VERSION 5.7 ;
  NOWIREEXTENSIONATPIN ON ;
  DIVIDERCHAR "/" ;
  BUSBITCHARS "[]" ;
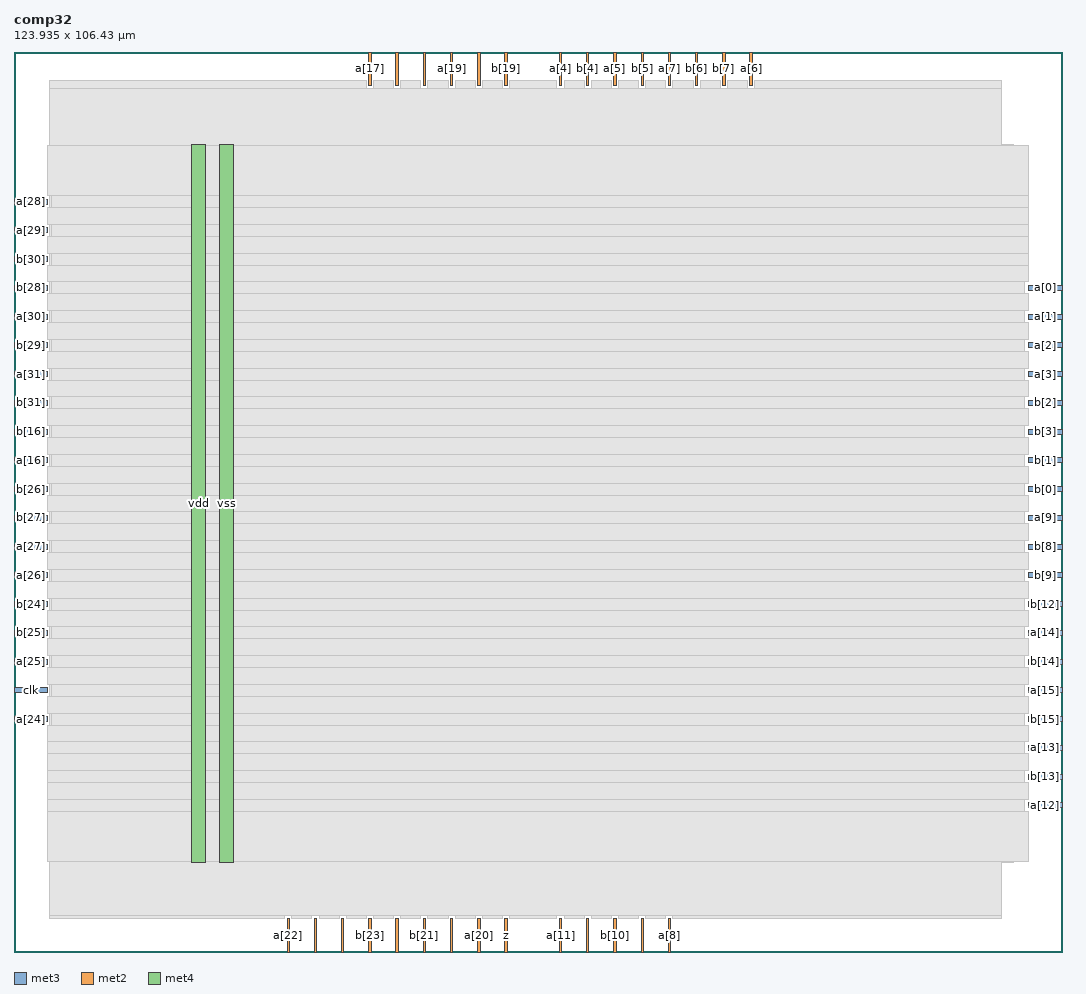
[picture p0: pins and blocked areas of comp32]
MACRO comp32
  CLASS BLOCK ;
  FOREIGN comp32 ;
  ORIGIN 0.000 0.000 ;
  SIZE 123.935 BY 106.430 ;
  PIN a[0]
    DIRECTION INPUT ;
    USE SIGNAL ;
    ANTENNAGATEAREA 0.196500 ;
    PORT
      LAYER met3 ;
        RECT 119.935 78.240 123.935 78.840 ;
    END
  END a[0]
  PIN a[10]
    DIRECTION INPUT ;
    USE SIGNAL ;
    ANTENNAGATEAREA 0.196500 ;
    PORT
      LAYER met2 ;
        RECT 74.150 0.000 74.430 4.000 ;
    END
  END a[10]
  PIN a[11]
    DIRECTION INPUT ;
    USE SIGNAL ;
    ANTENNAGATEAREA 0.196500 ;
    PORT
      LAYER met2 ;
        RECT 64.490 0.000 64.770 4.000 ;
    END
  END a[11]
  PIN a[12]
    DIRECTION INPUT ;
    USE SIGNAL ;
    ANTENNAGATEAREA 0.196500 ;
    PORT
      LAYER met3 ;
        RECT 119.935 17.040 123.935 17.640 ;
    END
  END a[12]
  PIN a[13]
    DIRECTION INPUT ;
    USE SIGNAL ;
    ANTENNAGATEAREA 0.196500 ;
    PORT
      LAYER met3 ;
        RECT 119.935 23.840 123.935 24.440 ;
    END
  END a[13]
  PIN a[14]
    DIRECTION INPUT ;
    USE SIGNAL ;
    ANTENNAGATEAREA 0.196500 ;
    PORT
      LAYER met3 ;
        RECT 119.935 37.440 123.935 38.040 ;
    END
  END a[14]
  PIN a[15]
    DIRECTION INPUT ;
    USE SIGNAL ;
    ANTENNAGATEAREA 0.196500 ;
    PORT
      LAYER met3 ;
        RECT 119.935 30.640 123.935 31.240 ;
    END
  END a[15]
  PIN a[16]
    DIRECTION INPUT ;
    USE SIGNAL ;
    ANTENNAGATEAREA 0.196500 ;
    PORT
      LAYER met3 ;
        RECT 0.000 57.840 4.000 58.440 ;
    END
  END a[16]
  PIN a[17]
    DIRECTION INPUT ;
    USE SIGNAL ;
    ANTENNAGATEAREA 0.196500 ;
    PORT
      LAYER met2 ;
        RECT 41.950 102.430 42.230 106.430 ;
    END
  END a[17]
  PIN a[18]
    DIRECTION INPUT ;
    USE SIGNAL ;
    ANTENNAGATEAREA 0.196500 ;
    PORT
      LAYER met2 ;
        RECT 45.170 102.430 45.450 106.430 ;
    END
  END a[18]
  PIN a[19]
    DIRECTION INPUT ;
    USE SIGNAL ;
    ANTENNAGATEAREA 0.196500 ;
    PORT
      LAYER met2 ;
        RECT 51.610 102.430 51.890 106.430 ;
    END
  END a[19]
  PIN a[1]
    DIRECTION INPUT ;
    USE SIGNAL ;
    ANTENNAGATEAREA 0.196500 ;
    PORT
      LAYER met3 ;
        RECT 119.935 74.840 123.935 75.440 ;
    END
  END a[1]
  PIN a[20]
    DIRECTION INPUT ;
    USE SIGNAL ;
    ANTENNAGATEAREA 0.196500 ;
    PORT
      LAYER met2 ;
        RECT 54.830 0.000 55.110 4.000 ;
    END
  END a[20]
  PIN a[21]
    DIRECTION INPUT ;
    USE SIGNAL ;
    ANTENNAGATEAREA 0.196500 ;
    PORT
      LAYER met2 ;
        RECT 51.610 0.000 51.890 4.000 ;
    END
  END a[21]
  PIN a[22]
    DIRECTION INPUT ;
    USE SIGNAL ;
    ANTENNAGATEAREA 0.196500 ;
    PORT
      LAYER met2 ;
        RECT 32.290 0.000 32.570 4.000 ;
    END
  END a[22]
  PIN a[23]
    DIRECTION INPUT ;
    USE SIGNAL ;
    ANTENNAGATEAREA 0.196500 ;
    PORT
      LAYER met2 ;
        RECT 35.510 0.000 35.790 4.000 ;
    END
  END a[23]
  PIN a[24]
    DIRECTION INPUT ;
    USE SIGNAL ;
    ANTENNAGATEAREA 0.196500 ;
    PORT
      LAYER met3 ;
        RECT 0.000 27.240 4.000 27.840 ;
    END
  END a[24]
  PIN a[25]
    DIRECTION INPUT ;
    USE SIGNAL ;
    ANTENNAGATEAREA 0.196500 ;
    PORT
      LAYER met3 ;
        RECT 0.000 34.040 4.000 34.640 ;
    END
  END a[25]
  PIN a[26]
    DIRECTION INPUT ;
    USE SIGNAL ;
    ANTENNAGATEAREA 0.196500 ;
    PORT
      LAYER met3 ;
        RECT 0.000 44.240 4.000 44.840 ;
    END
  END a[26]
  PIN a[27]
    DIRECTION INPUT ;
    USE SIGNAL ;
    ANTENNAGATEAREA 0.196500 ;
    PORT
      LAYER met3 ;
        RECT 0.000 47.640 4.000 48.240 ;
    END
  END a[27]
  PIN a[28]
    DIRECTION INPUT ;
    USE SIGNAL ;
    ANTENNAGATEAREA 0.196500 ;
    PORT
      LAYER met3 ;
        RECT 0.000 88.440 4.000 89.040 ;
    END
  END a[28]
  PIN a[29]
    DIRECTION INPUT ;
    USE SIGNAL ;
    ANTENNAGATEAREA 0.196500 ;
    PORT
      LAYER met3 ;
        RECT 0.000 85.040 4.000 85.640 ;
    END
  END a[29]
  PIN a[2]
    DIRECTION INPUT ;
    USE SIGNAL ;
    ANTENNAGATEAREA 0.196500 ;
    PORT
      LAYER met3 ;
        RECT 119.935 71.440 123.935 72.040 ;
    END
  END a[2]
  PIN a[30]
    DIRECTION INPUT ;
    USE SIGNAL ;
    ANTENNAGATEAREA 0.196500 ;
    PORT
      LAYER met3 ;
        RECT 0.000 74.840 4.000 75.440 ;
    END
  END a[30]
  PIN a[31]
    DIRECTION INPUT ;
    USE SIGNAL ;
    ANTENNAGATEAREA 0.196500 ;
    PORT
      LAYER met3 ;
        RECT 0.000 68.040 4.000 68.640 ;
    END
  END a[31]
  PIN a[3]
    DIRECTION INPUT ;
    USE SIGNAL ;
    ANTENNAGATEAREA 0.196500 ;
    PORT
      LAYER met3 ;
        RECT 119.935 68.040 123.935 68.640 ;
    END
  END a[3]
  PIN a[4]
    DIRECTION INPUT ;
    USE SIGNAL ;
    ANTENNAGATEAREA 0.196500 ;
    PORT
      LAYER met2 ;
        RECT 64.490 102.430 64.770 106.430 ;
    END
  END a[4]
  PIN a[5]
    DIRECTION INPUT ;
    USE SIGNAL ;
    ANTENNAGATEAREA 0.196500 ;
    PORT
      LAYER met2 ;
        RECT 70.930 102.430 71.210 106.430 ;
    END
  END a[5]
  PIN a[6]
    DIRECTION INPUT ;
    USE SIGNAL ;
    ANTENNAGATEAREA 0.196500 ;
    PORT
      LAYER met2 ;
        RECT 87.030 102.430 87.310 106.430 ;
    END
  END a[6]
  PIN a[7]
    DIRECTION INPUT ;
    USE SIGNAL ;
    ANTENNAGATEAREA 0.196500 ;
    PORT
      LAYER met2 ;
        RECT 77.370 102.430 77.650 106.430 ;
    END
  END a[7]
  PIN a[8]
    DIRECTION INPUT ;
    USE SIGNAL ;
    ANTENNAGATEAREA 0.196500 ;
    PORT
      LAYER met2 ;
        RECT 77.370 0.000 77.650 4.000 ;
    END
  END a[8]
  PIN a[9]
    DIRECTION INPUT ;
    USE SIGNAL ;
    ANTENNAGATEAREA 0.196500 ;
    PORT
      LAYER met3 ;
        RECT 119.935 51.040 123.935 51.640 ;
    END
  END a[9]
  PIN b[0]
    DIRECTION INPUT ;
    USE SIGNAL ;
    ANTENNAGATEAREA 0.196500 ;
    PORT
      LAYER met3 ;
        RECT 119.935 54.440 123.935 55.040 ;
    END
  END b[0]
  PIN b[10]
    DIRECTION INPUT ;
    USE SIGNAL ;
    ANTENNAGATEAREA 0.196500 ;
    PORT
      LAYER met2 ;
        RECT 70.930 0.000 71.210 4.000 ;
    END
  END b[10]
  PIN b[11]
    DIRECTION INPUT ;
    USE SIGNAL ;
    ANTENNAGATEAREA 0.196500 ;
    PORT
      LAYER met2 ;
        RECT 67.710 0.000 67.990 4.000 ;
    END
  END b[11]
  PIN b[12]
    DIRECTION INPUT ;
    USE SIGNAL ;
    ANTENNAGATEAREA 0.196500 ;
    PORT
      LAYER met3 ;
        RECT 119.935 40.840 123.935 41.440 ;
    END
  END b[12]
  PIN b[13]
    DIRECTION INPUT ;
    USE SIGNAL ;
    ANTENNAGATEAREA 0.196500 ;
    PORT
      LAYER met3 ;
        RECT 119.935 20.440 123.935 21.040 ;
    END
  END b[13]
  PIN b[14]
    DIRECTION INPUT ;
    USE SIGNAL ;
    ANTENNAGATEAREA 0.196500 ;
    PORT
      LAYER met3 ;
        RECT 119.935 34.040 123.935 34.640 ;
    END
  END b[14]
  PIN b[15]
    DIRECTION INPUT ;
    USE SIGNAL ;
    ANTENNAGATEAREA 0.196500 ;
    PORT
      LAYER met3 ;
        RECT 119.935 27.240 123.935 27.840 ;
    END
  END b[15]
  PIN b[16]
    DIRECTION INPUT ;
    USE SIGNAL ;
    ANTENNAGATEAREA 0.196500 ;
    PORT
      LAYER met3 ;
        RECT 0.000 61.240 4.000 61.840 ;
    END
  END b[16]
  PIN b[17]
    DIRECTION INPUT ;
    USE SIGNAL ;
    ANTENNAGATEAREA 0.196500 ;
    PORT
      LAYER met2 ;
        RECT 48.390 102.430 48.670 106.430 ;
    END
  END b[17]
  PIN b[18]
    DIRECTION INPUT ;
    USE SIGNAL ;
    ANTENNAGATEAREA 0.196500 ;
    PORT
      LAYER met2 ;
        RECT 54.830 102.430 55.110 106.430 ;
    END
  END b[18]
  PIN b[19]
    DIRECTION INPUT ;
    USE SIGNAL ;
    ANTENNAGATEAREA 0.196500 ;
    PORT
      LAYER met2 ;
        RECT 58.050 102.430 58.330 106.430 ;
    END
  END b[19]
  PIN b[1]
    DIRECTION INPUT ;
    USE SIGNAL ;
    ANTENNAGATEAREA 0.196500 ;
    PORT
      LAYER met3 ;
        RECT 119.935 57.840 123.935 58.440 ;
    END
  END b[1]
  PIN b[20]
    DIRECTION INPUT ;
    USE SIGNAL ;
    ANTENNAGATEAREA 0.196500 ;
    PORT
      LAYER met2 ;
        RECT 45.170 0.000 45.450 4.000 ;
    END
  END b[20]
  PIN b[21]
    DIRECTION INPUT ;
    USE SIGNAL ;
    ANTENNAGATEAREA 0.196500 ;
    PORT
      LAYER met2 ;
        RECT 48.390 0.000 48.670 4.000 ;
    END
  END b[21]
  PIN b[22]
    DIRECTION INPUT ;
    USE SIGNAL ;
    ANTENNAGATEAREA 0.196500 ;
    PORT
      LAYER met2 ;
        RECT 38.730 0.000 39.010 4.000 ;
    END
  END b[22]
  PIN b[23]
    DIRECTION INPUT ;
    USE SIGNAL ;
    ANTENNAGATEAREA 0.196500 ;
    PORT
      LAYER met2 ;
        RECT 41.950 0.000 42.230 4.000 ;
    END
  END b[23]
  PIN b[24]
    DIRECTION INPUT ;
    USE SIGNAL ;
    ANTENNAGATEAREA 0.196500 ;
    PORT
      LAYER met3 ;
        RECT 0.000 40.840 4.000 41.440 ;
    END
  END b[24]
  PIN b[25]
    DIRECTION INPUT ;
    USE SIGNAL ;
    ANTENNAGATEAREA 0.196500 ;
    PORT
      LAYER met3 ;
        RECT 0.000 37.440 4.000 38.040 ;
    END
  END b[25]
  PIN b[26]
    DIRECTION INPUT ;
    USE SIGNAL ;
    ANTENNAGATEAREA 0.196500 ;
    PORT
      LAYER met3 ;
        RECT 0.000 54.440 4.000 55.040 ;
    END
  END b[26]
  PIN b[27]
    DIRECTION INPUT ;
    USE SIGNAL ;
    ANTENNAGATEAREA 0.196500 ;
    PORT
      LAYER met3 ;
        RECT 0.000 51.040 4.000 51.640 ;
    END
  END b[27]
  PIN b[28]
    DIRECTION INPUT ;
    USE SIGNAL ;
    ANTENNAGATEAREA 0.196500 ;
    PORT
      LAYER met3 ;
        RECT 0.000 78.240 4.000 78.840 ;
    END
  END b[28]
  PIN b[29]
    DIRECTION INPUT ;
    USE SIGNAL ;
    ANTENNAGATEAREA 0.196500 ;
    PORT
      LAYER met3 ;
        RECT 0.000 71.440 4.000 72.040 ;
    END
  END b[29]
  PIN b[2]
    DIRECTION INPUT ;
    USE SIGNAL ;
    ANTENNAGATEAREA 0.196500 ;
    PORT
      LAYER met3 ;
        RECT 119.935 64.640 123.935 65.240 ;
    END
  END b[2]
  PIN b[30]
    DIRECTION INPUT ;
    USE SIGNAL ;
    ANTENNAGATEAREA 0.196500 ;
    PORT
      LAYER met3 ;
        RECT 0.000 81.640 4.000 82.240 ;
    END
  END b[30]
  PIN b[31]
    DIRECTION INPUT ;
    USE SIGNAL ;
    ANTENNAGATEAREA 0.196500 ;
    PORT
      LAYER met3 ;
        RECT 0.000 64.640 4.000 65.240 ;
    END
  END b[31]
  PIN b[3]
    DIRECTION INPUT ;
    USE SIGNAL ;
    ANTENNAGATEAREA 0.196500 ;
    PORT
      LAYER met3 ;
        RECT 119.935 61.240 123.935 61.840 ;
    END
  END b[3]
  PIN b[4]
    DIRECTION INPUT ;
    USE SIGNAL ;
    ANTENNAGATEAREA 0.196500 ;
    PORT
      LAYER met2 ;
        RECT 67.710 102.430 67.990 106.430 ;
    END
  END b[4]
  PIN b[5]
    DIRECTION INPUT ;
    USE SIGNAL ;
    ANTENNAGATEAREA 0.196500 ;
    PORT
      LAYER met2 ;
        RECT 74.150 102.430 74.430 106.430 ;
    END
  END b[5]
  PIN b[6]
    DIRECTION INPUT ;
    USE SIGNAL ;
    ANTENNAGATEAREA 0.196500 ;
    PORT
      LAYER met2 ;
        RECT 80.590 102.430 80.870 106.430 ;
    END
  END b[6]
  PIN b[7]
    DIRECTION INPUT ;
    USE SIGNAL ;
    ANTENNAGATEAREA 0.196500 ;
    PORT
      LAYER met2 ;
        RECT 83.810 102.430 84.090 106.430 ;
    END
  END b[7]
  PIN b[8]
    DIRECTION INPUT ;
    USE SIGNAL ;
    ANTENNAGATEAREA 0.196500 ;
    PORT
      LAYER met3 ;
        RECT 119.935 47.640 123.935 48.240 ;
    END
  END b[8]
  PIN b[9]
    DIRECTION INPUT ;
    USE SIGNAL ;
    ANTENNAGATEAREA 0.196500 ;
    PORT
      LAYER met3 ;
        RECT 119.935 44.240 123.935 44.840 ;
    END
  END b[9]
  PIN clk
    DIRECTION INPUT ;
    USE SIGNAL ;
    ANTENNAGATEAREA 0.159000 ;
    PORT
      LAYER met3 ;
        RECT 0.000 30.640 4.000 31.240 ;
    END
  END clk
  PIN vdd
    DIRECTION INOUT ;
    USE POWER ;
    PORT
      LAYER met4 ;
        RECT 21.040 10.640 22.640 95.440 ;
    END
  END vdd
  PIN vss
    DIRECTION INOUT ;
    USE GROUND ;
    PORT
      LAYER met4 ;
        RECT 24.340 10.640 25.940 95.440 ;
    END
  END vss
  PIN z
    DIRECTION OUTPUT ;
    USE SIGNAL ;
    ANTENNADIFFAREA 0.445500 ;
    PORT
      LAYER met2 ;
        RECT 58.050 0.000 58.330 4.000 ;
    END
  END z
  OBS
      LAYER li1 ;
        RECT 5.520 10.795 118.220 95.285 ;
      LAYER met1 ;
        RECT 4.210 10.640 118.220 95.440 ;
      LAYER met2 ;
        RECT 4.230 102.150 41.670 103.090 ;
        RECT 42.510 102.150 44.890 103.090 ;
        RECT 45.730 102.150 48.110 103.090 ;
        RECT 48.950 102.150 51.330 103.090 ;
        RECT 52.170 102.150 54.550 103.090 ;
        RECT 55.390 102.150 57.770 103.090 ;
        RECT 58.610 102.150 64.210 103.090 ;
        RECT 65.050 102.150 67.430 103.090 ;
        RECT 68.270 102.150 70.650 103.090 ;
        RECT 71.490 102.150 73.870 103.090 ;
        RECT 74.710 102.150 77.090 103.090 ;
        RECT 77.930 102.150 80.310 103.090 ;
        RECT 81.150 102.150 83.530 103.090 ;
        RECT 84.370 102.150 86.750 103.090 ;
        RECT 87.590 102.150 116.750 103.090 ;
        RECT 4.230 4.280 116.750 102.150 ;
        RECT 4.230 4.000 32.010 4.280 ;
        RECT 32.850 4.000 35.230 4.280 ;
        RECT 36.070 4.000 38.450 4.280 ;
        RECT 39.290 4.000 41.670 4.280 ;
        RECT 42.510 4.000 44.890 4.280 ;
        RECT 45.730 4.000 48.110 4.280 ;
        RECT 48.950 4.000 51.330 4.280 ;
        RECT 52.170 4.000 54.550 4.280 ;
        RECT 55.390 4.000 57.770 4.280 ;
        RECT 58.610 4.000 64.210 4.280 ;
        RECT 65.050 4.000 67.430 4.280 ;
        RECT 68.270 4.000 70.650 4.280 ;
        RECT 71.490 4.000 73.870 4.280 ;
        RECT 74.710 4.000 77.090 4.280 ;
        RECT 77.930 4.000 116.750 4.280 ;
      LAYER met3 ;
        RECT 3.990 89.440 119.935 95.365 ;
        RECT 4.400 88.040 119.935 89.440 ;
        RECT 3.990 86.040 119.935 88.040 ;
        RECT 4.400 84.640 119.935 86.040 ;
        RECT 3.990 82.640 119.935 84.640 ;
        RECT 4.400 81.240 119.935 82.640 ;
        RECT 3.990 79.240 119.935 81.240 ;
        RECT 4.400 77.840 119.535 79.240 ;
        RECT 3.990 75.840 119.935 77.840 ;
        RECT 4.400 74.440 119.535 75.840 ;
        RECT 3.990 72.440 119.935 74.440 ;
        RECT 4.400 71.040 119.535 72.440 ;
        RECT 3.990 69.040 119.935 71.040 ;
        RECT 4.400 67.640 119.535 69.040 ;
        RECT 3.990 65.640 119.935 67.640 ;
        RECT 4.400 64.240 119.535 65.640 ;
        RECT 3.990 62.240 119.935 64.240 ;
        RECT 4.400 60.840 119.535 62.240 ;
        RECT 3.990 58.840 119.935 60.840 ;
        RECT 4.400 57.440 119.535 58.840 ;
        RECT 3.990 55.440 119.935 57.440 ;
        RECT 4.400 54.040 119.535 55.440 ;
        RECT 3.990 52.040 119.935 54.040 ;
        RECT 4.400 50.640 119.535 52.040 ;
        RECT 3.990 48.640 119.935 50.640 ;
        RECT 4.400 47.240 119.535 48.640 ;
        RECT 3.990 45.240 119.935 47.240 ;
        RECT 4.400 43.840 119.535 45.240 ;
        RECT 3.990 41.840 119.935 43.840 ;
        RECT 4.400 40.440 119.535 41.840 ;
        RECT 3.990 38.440 119.935 40.440 ;
        RECT 4.400 37.040 119.535 38.440 ;
        RECT 3.990 35.040 119.935 37.040 ;
        RECT 4.400 33.640 119.535 35.040 ;
        RECT 3.990 31.640 119.935 33.640 ;
        RECT 4.400 30.240 119.535 31.640 ;
        RECT 3.990 28.240 119.935 30.240 ;
        RECT 4.400 26.840 119.535 28.240 ;
        RECT 3.990 24.840 119.935 26.840 ;
        RECT 3.990 23.440 119.535 24.840 ;
        RECT 3.990 21.440 119.935 23.440 ;
        RECT 3.990 20.040 119.535 21.440 ;
        RECT 3.990 18.040 119.935 20.040 ;
        RECT 3.990 16.640 119.535 18.040 ;
        RECT 3.990 10.715 119.935 16.640 ;
  END
END comp32
END LIBRARY

